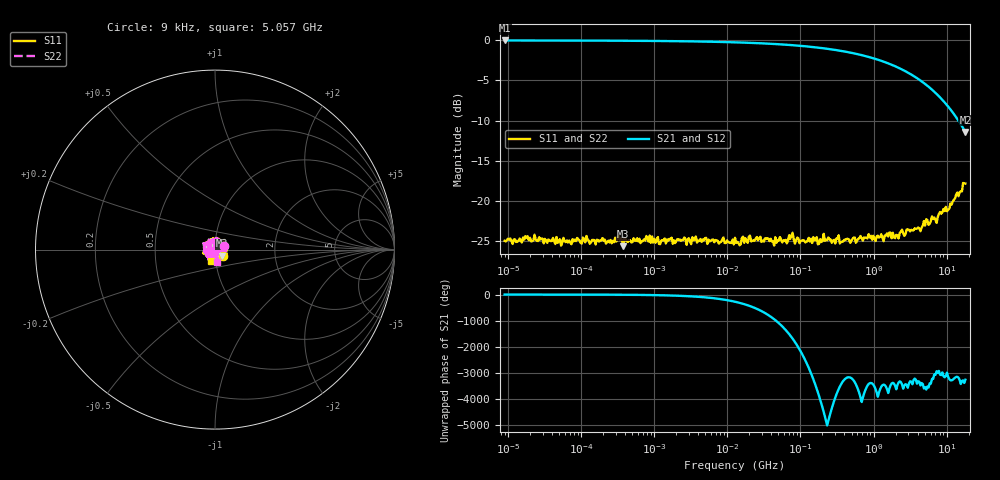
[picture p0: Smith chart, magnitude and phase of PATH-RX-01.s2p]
! CAL-ELEKTRA — DATOS SINTÉTICOS DE EJEMPLO: no son una medida real.
! Cable simulado PATH-RX-01: 15.0 m, 9 kHz – 18 GHz
# HZ S RI R 50
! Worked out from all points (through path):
!   401 points, 9 kHz to 18 GHz, reference 50 ohm
!   highest |S21| = -0.01 dB at 9 kHz (marker M1); lowest = -11.4 dB at 18 GHz (marker M2)
!   lowest |S11| = -25.7 dB at 377.4 kHz (marker M3), VSWR 1.11, Z = 54 - j3.65 ohm
!   |S11| at or under -10 dB: start of sweep to end of sweep
!   |S22| runs from -25.7 to -17.8 dB; largest |S21 - S12| = 0
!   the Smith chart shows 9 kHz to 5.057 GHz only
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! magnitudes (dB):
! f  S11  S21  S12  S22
! 9 kHz  -25.0  0.0  0.0  -25.0
! 14.42 kHz  -24.7  0.0  0.0  -24.7
! 17.29 kHz  -24.4  0.0  0.0  -24.4
! 51.33 kHz  -24.8  0.0  0.0  -24.8
! 102.3 kHz  -25.3  0.0  0.0  -25.3
! 377.4 kHz  -25.7  0.0  0.0  -25.7
! 808.3 kHz  -24.7  -0.1  -0.1  -24.7
! 1.162 MHz  -25.4  -0.1  -0.1  -25.4
! 3.576 MHz  -24.8  -0.1  -0.1  -24.8
! 13.2 MHz  -25.3  -0.2  -0.2  -25.3
! 26.29 MHz  -24.9  -0.3  -0.3  -24.9
! 60.55 MHz  -25.0  -0.5  -0.5  -25.0
! 75.27 MHz  -24.4  -0.6  -0.6  -24.4
! 90.24 MHz  -24.6  -0.6  -0.6  -24.6
! 144.6 MHz  -25.3  -0.8  -0.8  -25.3
! 371.3 MHz  -25.1  -1.3  -1.3  -25.1
! 1.643 GHz  -24.0  -2.9  -2.9  -24.0
! 2.042 GHz  -24.3  -3.3  -3.3  -24.3
! 3.923 GHz  -23.5  -4.7  -4.7  -23.5
! 7.01 GHz  -22.4  -6.5  -6.5  -22.4
! 10.83 GHz  -21.0  -8.4  -8.4  -21.0
! 18 GHz  -17.9  -11.4  -11.4  -17.9
